VERSION 5.7 ;
  NOWIREEXTENSIONATPIN ON ;
  DIVIDERCHAR "/" ;
  BUSBITCHARS "[]" ;
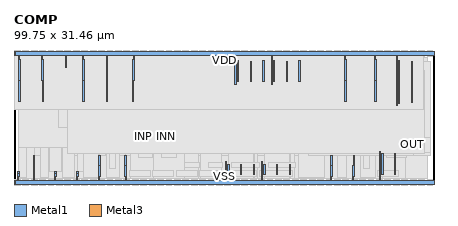
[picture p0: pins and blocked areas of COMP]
MACRO COMP
  CLASS BLOCK ;
  FOREIGN COMP ;
  ORIGIN 1.260 0.000 ;
  SIZE 99.750 BY 31.460 ;
  PIN VSS
    DIRECTION INOUT ;
    USE GROUND ;
    PORT
      LAYER Metal1 ;
        RECT 3.300 4.380 3.660 6.880 ;
        RECT 18.900 4.380 19.260 6.880 ;
        RECT -0.360 2.380 0.000 2.880 ;
        RECT -0.390 1.880 0.000 2.380 ;
        RECT 3.270 1.880 3.660 4.380 ;
        RECT 8.460 2.380 8.820 2.880 ;
        RECT 13.620 2.380 13.980 2.880 ;
        RECT 8.430 1.880 8.820 2.380 ;
        RECT 13.590 1.880 13.980 2.380 ;
        RECT 18.870 1.880 19.260 4.380 ;
        RECT 25.060 4.380 25.420 6.880 ;
        RECT 25.060 1.880 25.450 4.380 ;
        RECT -0.390 0.900 -0.160 1.880 ;
        RECT 3.270 0.900 3.500 1.880 ;
        RECT 8.430 0.900 8.660 1.880 ;
        RECT 13.590 0.900 13.820 1.880 ;
        RECT 18.870 0.900 19.100 1.880 ;
        RECT 25.220 0.900 25.450 1.880 ;
        RECT 48.910 1.650 49.210 5.310 ;
        RECT 49.460 2.230 49.820 4.730 ;
        RECT 52.520 2.250 52.820 4.710 ;
        RECT 55.520 2.230 55.880 4.730 ;
        RECT 57.510 1.650 57.810 5.310 ;
        RECT 58.060 2.230 58.420 4.730 ;
        RECT 61.120 2.250 61.420 4.710 ;
        RECT 64.120 2.230 64.480 4.730 ;
        RECT 73.980 4.380 74.340 6.880 ;
        RECT 79.260 4.380 79.620 6.880 ;
        RECT 73.950 1.880 74.340 4.380 ;
        RECT 79.230 1.880 79.620 4.380 ;
        RECT 48.945 0.900 49.175 1.650 ;
        RECT 57.545 0.900 57.775 1.650 ;
        RECT 73.950 0.900 74.180 1.880 ;
        RECT 79.230 0.900 79.460 1.880 ;
        RECT 85.530 1.650 85.830 7.810 ;
        RECT 86.080 2.230 86.440 7.230 ;
        RECT 89.140 2.250 89.440 7.210 ;
        RECT 85.565 0.900 85.795 1.650 ;
        RECT -1.000 0.000 98.490 0.900 ;
      LAYER Metal3 ;
        RECT -1.260 0.000 98.490 0.900 ;
    END
  END VSS
  PIN VDD
    DIRECTION INOUT ;
    USE POWER ;
    PORT
      LAYER Metal1 ;
        RECT -1.000 30.560 98.490 31.460 ;
        RECT -0.190 29.580 0.040 30.560 ;
        RECT 4.050 30.460 4.530 30.560 ;
        RECT 5.370 29.580 5.600 30.560 ;
        RECT 10.930 29.580 11.160 30.560 ;
        RECT 13.670 30.460 14.150 30.560 ;
        RECT 14.990 29.580 15.220 30.560 ;
        RECT 20.670 29.580 20.900 30.560 ;
        RECT 27.020 29.580 27.250 30.560 ;
        RECT 28.070 30.460 28.550 30.560 ;
        RECT 39.230 30.460 39.710 30.560 ;
        RECT 50.390 30.460 50.870 30.560 ;
        RECT 51.225 29.810 51.455 30.560 ;
        RECT 59.010 30.460 59.490 30.560 ;
        RECT 59.845 29.810 60.075 30.560 ;
        RECT 67.630 30.460 68.110 30.560 ;
        RECT 75.780 30.460 76.260 30.560 ;
        RECT -0.190 24.580 0.200 29.580 ;
        RECT 5.370 24.580 5.760 29.580 ;
        RECT 10.930 28.580 11.320 29.580 ;
        RECT 10.960 27.580 11.320 28.580 ;
        RECT 14.990 24.580 15.380 29.580 ;
        RECT 20.670 24.580 21.060 29.580 ;
        RECT -0.160 19.580 0.200 24.580 ;
        RECT 5.400 19.580 5.760 24.580 ;
        RECT 15.020 19.580 15.380 24.580 ;
        RECT 20.700 19.580 21.060 24.580 ;
        RECT 26.860 24.580 27.250 29.580 ;
        RECT 26.860 19.580 27.220 24.580 ;
        RECT 51.190 23.650 51.490 29.810 ;
        RECT 51.740 24.230 52.100 29.230 ;
        RECT 54.800 24.250 55.100 29.210 ;
        RECT 57.800 24.230 58.160 29.230 ;
        RECT 59.810 23.650 60.110 29.810 ;
        RECT 77.220 29.580 77.450 30.560 ;
        RECT 83.120 30.460 83.600 30.560 ;
        RECT 84.440 29.580 84.670 30.560 ;
        RECT 89.515 29.810 89.745 30.560 ;
        RECT 60.360 24.230 60.720 29.230 ;
        RECT 63.420 24.250 63.720 29.210 ;
        RECT 66.420 24.230 66.780 29.230 ;
        RECT 77.220 24.580 77.610 29.580 ;
        RECT 84.440 24.580 84.830 29.580 ;
        RECT 77.250 19.580 77.610 24.580 ;
        RECT 84.470 19.580 84.830 24.580 ;
        RECT 89.480 18.650 89.780 29.810 ;
        RECT 90.030 19.230 90.390 29.230 ;
        RECT 93.090 19.250 93.390 29.210 ;
      LAYER Metal3 ;
        RECT -1.260 30.560 98.490 31.460 ;
    END
  END VDD
  PIN OUT
    DIRECTION INOUT ;
    ANTENNADIFFAREA 14.400000 ;
    PORT
      LAYER Metal3 ;
      RECT 90.855 9.070 91.255 9.470 ;
      RECT 91.955 9.070 94.855 9.470 ;
      RECT 95.455 9.070 95.855 9.470 ;
    END
  END OUT
  PIN INP
    DIRECTION INPUT ;
    ANTENNAGATEAREA 30.000000 ;
    PORT
      LAYER Metal3 ;
      RECT 28.030 11.050 30.730 11.450 ;
    END
  END INP
  PIN INN
    DIRECTION INPUT ;
    ANTENNAGATEAREA 30.000000 ;
    PORT
      LAYER Metal3 ;
      RECT 33.550 11.050 36.250 11.450 ;
    END
  END INN
  OBS
      LAYER Via1 ;
        RECT -0.160 1.420 96.845 30.040 ;
        RECT 48.850 30.320 50.230 31.700 ;
        RECT 50.850 30.320 52.230 31.700 ;
        RECT 52.850 30.320 54.230 31.700 ;
        RECT 54.850 30.320 56.230 31.700 ;
        RECT 56.850 30.320 58.230 31.700 ;
        RECT 58.850 30.320 60.230 31.700 ;
        RECT 60.850 30.320 62.230 31.700 ;
        RECT 62.850 30.320 64.230 31.700 ;
        RECT 64.850 30.320 66.230 31.700 ;
        RECT 66.850 30.320 68.230 31.700 ;
        RECT 68.850 30.320 70.230 31.700 ;
        RECT 70.850 30.320 72.230 31.700 ;
        RECT 72.850 30.320 74.230 31.700 ;
        RECT 74.850 30.320 76.230 31.700 ;
        RECT 76.850 30.320 78.230 31.700 ;
        RECT 78.850 30.320 80.230 31.700 ;
        RECT 80.850 30.320 82.230 31.700 ;
        RECT 82.850 30.320 84.230 31.700 ;
        RECT 84.850 30.320 86.230 31.700 ;
        RECT 86.850 30.320 88.230 31.700 ;
        RECT 88.850 30.320 90.230 31.700 ;
        RECT 90.850 30.320 92.230 31.700 ;
        RECT 92.850 30.320 94.230 31.700 ;
        RECT 94.850 30.320 96.230 31.700 ;
        RECT 96.850 30.320 98.230 31.700 ;
        RECT -1.150 30.320 0.230 31.700 ;
        RECT 0.850 30.320 2.230 31.700 ;
        RECT 2.850 30.320 4.230 31.700 ;
        RECT 4.850 30.320 6.230 31.700 ;
        RECT 6.850 30.320 8.230 31.700 ;
        RECT 8.850 30.320 10.230 31.700 ;
        RECT 10.850 30.320 12.230 31.700 ;
        RECT 12.850 30.320 14.230 31.700 ;
        RECT 14.850 30.320 16.230 31.700 ;
        RECT 16.850 30.320 18.230 31.700 ;
        RECT 18.850 30.320 20.230 31.700 ;
        RECT 20.850 30.320 22.230 31.700 ;
        RECT 22.850 30.320 24.230 31.700 ;
        RECT 24.850 30.320 26.230 31.700 ;
        RECT 26.850 30.320 28.230 31.700 ;
        RECT 28.850 30.320 30.230 31.700 ;
        RECT 30.850 30.320 32.230 31.700 ;
        RECT 32.850 30.320 34.230 31.700 ;
        RECT 34.850 30.320 36.230 31.700 ;
        RECT 36.850 30.320 38.230 31.700 ;
        RECT 38.850 30.320 40.230 31.700 ;
        RECT 40.850 30.320 42.230 31.700 ;
        RECT 42.850 30.320 44.230 31.700 ;
        RECT 44.850 30.320 46.230 31.700 ;
        RECT 46.850 30.320 48.230 31.700 ;
        RECT 0.850 -0.240 2.230 1.140 ;
        RECT 2.850 -0.240 4.230 1.140 ;
        RECT 4.850 -0.240 6.230 1.140 ;
        RECT 6.850 -0.240 8.230 1.140 ;
        RECT 8.850 -0.240 10.230 1.140 ;
        RECT 10.850 -0.240 12.230 1.140 ;
        RECT 12.850 -0.240 14.230 1.140 ;
        RECT 14.850 -0.240 16.230 1.140 ;
        RECT 16.850 -0.240 18.230 1.140 ;
        RECT 18.850 -0.240 20.230 1.140 ;
        RECT 20.850 -0.240 22.230 1.140 ;
        RECT 22.850 -0.240 24.230 1.140 ;
        RECT 24.850 -0.240 26.230 1.140 ;
        RECT 26.850 -0.240 28.230 1.140 ;
        RECT 28.850 -0.240 30.230 1.140 ;
        RECT 30.850 -0.240 32.230 1.140 ;
        RECT 32.850 -0.240 34.230 1.140 ;
        RECT 34.850 -0.240 36.230 1.140 ;
        RECT 36.850 -0.240 38.230 1.140 ;
        RECT 38.850 -0.240 40.230 1.140 ;
        RECT 40.850 -0.240 42.230 1.140 ;
        RECT 42.850 -0.240 44.230 1.140 ;
        RECT 44.850 -0.240 46.230 1.140 ;
        RECT 46.850 -0.240 48.230 1.140 ;
        RECT -1.150 -0.240 0.230 1.140 ;
        RECT 50.850 -0.240 52.230 1.140 ;
        RECT 52.850 -0.240 54.230 1.140 ;
        RECT 54.850 -0.240 56.230 1.140 ;
        RECT 56.850 -0.240 58.230 1.140 ;
        RECT 58.850 -0.240 60.230 1.140 ;
        RECT 60.850 -0.240 62.230 1.140 ;
        RECT 62.850 -0.240 64.230 1.140 ;
        RECT 64.850 -0.240 66.230 1.140 ;
        RECT 66.850 -0.240 68.230 1.140 ;
        RECT 68.850 -0.240 70.230 1.140 ;
        RECT 70.850 -0.240 72.230 1.140 ;
        RECT 72.850 -0.240 74.230 1.140 ;
        RECT 74.850 -0.240 76.230 1.140 ;
        RECT 76.850 -0.240 78.230 1.140 ;
        RECT 78.850 -0.240 80.230 1.140 ;
        RECT 80.850 -0.240 82.230 1.140 ;
        RECT 82.850 -0.240 84.230 1.140 ;
        RECT 84.850 -0.240 86.230 1.140 ;
        RECT 86.850 -0.240 88.230 1.140 ;
        RECT 88.850 -0.240 90.230 1.140 ;
        RECT 90.850 -0.240 92.230 1.140 ;
        RECT 92.850 -0.240 94.230 1.140 ;
        RECT 94.850 -0.240 96.230 1.140 ;
        RECT 96.850 -0.240 98.230 1.140 ;
        RECT 48.850 -0.240 50.230 1.140 ;
      LAYER Via2 ;
        RECT 48.380 1.820 56.380 3.140 ;
        RECT -0.110 8.590 93.160 17.870 ;
        RECT 45.080 23.820 50.040 25.140 ;
        RECT 47.170 28.320 50.620 29.640 ;
        RECT 50.660 23.820 58.660 25.140 ;
        RECT 59.280 23.820 67.280 25.140 ;
        RECT 79.845 17.920 81.205 25.260 ;
        RECT 88.950 18.820 93.920 20.140 ;
        RECT 52.750 28.320 59.240 29.640 ;
        RECT 61.370 28.320 67.860 29.640 ;
        RECT 91.040 28.320 96.010 29.640 ;
        RECT 48.850 30.320 50.230 31.700 ;
        RECT 50.850 30.320 52.230 31.700 ;
        RECT 52.850 30.320 54.230 31.700 ;
        RECT 54.850 30.320 56.230 31.700 ;
        RECT 56.850 30.320 58.230 31.700 ;
        RECT 58.850 30.320 60.230 31.700 ;
        RECT 60.850 30.320 62.230 31.700 ;
        RECT 62.850 30.320 64.230 31.700 ;
        RECT 64.850 30.320 66.230 31.700 ;
        RECT 66.850 30.320 68.230 31.700 ;
        RECT 68.850 30.320 70.230 31.700 ;
        RECT 70.850 30.320 72.230 31.700 ;
        RECT 72.850 30.320 74.230 31.700 ;
        RECT 74.850 30.320 76.230 31.700 ;
        RECT 76.850 30.320 78.230 31.700 ;
        RECT 78.850 30.320 80.230 31.700 ;
        RECT 80.850 30.320 82.230 31.700 ;
        RECT 82.850 30.320 84.230 31.700 ;
        RECT 84.850 30.320 86.230 31.700 ;
        RECT 86.850 30.320 88.230 31.700 ;
        RECT 88.850 30.320 90.230 31.700 ;
        RECT 90.850 30.320 92.230 31.700 ;
        RECT 92.850 30.320 94.230 31.700 ;
        RECT 94.850 30.320 96.230 31.700 ;
        RECT 96.850 30.320 98.230 31.700 ;
        RECT 34.850 30.320 36.230 31.700 ;
        RECT 36.850 30.320 38.230 31.700 ;
        RECT 38.850 30.320 40.230 31.700 ;
        RECT 40.850 30.320 42.230 31.700 ;
        RECT 42.850 30.320 44.230 31.700 ;
        RECT 44.850 30.320 46.230 31.700 ;
        RECT 46.850 30.320 48.230 31.700 ;
        RECT 30.430 28.320 33.880 29.640 ;
        RECT 36.010 28.320 39.460 29.640 ;
        RECT 41.590 28.320 45.040 29.640 ;
        RECT 28.340 18.820 33.300 20.140 ;
        RECT 39.500 23.820 44.460 25.140 ;
        RECT 23.295 17.920 24.655 25.260 ;
        RECT 33.920 18.820 38.880 20.140 ;
        RECT -1.150 30.320 0.230 31.700 ;
        RECT 0.850 30.320 2.230 31.700 ;
        RECT 2.850 30.320 4.230 31.700 ;
        RECT 4.850 30.320 6.230 31.700 ;
        RECT 6.850 30.320 8.230 31.700 ;
        RECT 8.850 30.320 10.230 31.700 ;
        RECT 10.850 30.320 12.230 31.700 ;
        RECT 12.850 30.320 14.230 31.700 ;
        RECT 14.850 30.320 16.230 31.700 ;
        RECT 16.850 30.320 18.230 31.700 ;
        RECT 18.850 30.320 20.230 31.700 ;
        RECT 20.850 30.320 22.230 31.700 ;
        RECT 22.850 30.320 24.230 31.700 ;
        RECT 24.850 30.320 26.230 31.700 ;
        RECT 26.850 30.320 28.230 31.700 ;
        RECT 28.850 30.320 30.230 31.700 ;
        RECT 30.850 30.320 32.230 31.700 ;
        RECT 32.850 30.320 34.230 31.700 ;
        RECT 21.495 3.700 22.855 8.540 ;
        RECT 0.850 -0.240 2.230 1.140 ;
        RECT 2.850 -0.240 4.230 1.140 ;
        RECT 4.850 -0.240 6.230 1.140 ;
        RECT 6.850 -0.240 8.230 1.140 ;
        RECT 8.850 -0.240 10.230 1.140 ;
        RECT 10.850 -0.240 12.230 1.140 ;
        RECT 12.850 -0.240 14.230 1.140 ;
        RECT 14.850 -0.240 16.230 1.140 ;
        RECT 16.850 -0.240 18.230 1.140 ;
        RECT 18.850 -0.240 20.230 1.140 ;
        RECT 20.850 -0.240 22.230 1.140 ;
        RECT 22.850 -0.240 24.230 1.140 ;
        RECT 24.850 -0.240 26.230 1.140 ;
        RECT 26.850 -0.240 28.230 1.140 ;
        RECT 28.850 -0.240 30.230 1.140 ;
        RECT 30.850 -0.240 32.230 1.140 ;
        RECT 32.850 -0.240 34.230 1.140 ;
        RECT 34.850 -0.240 36.230 1.140 ;
        RECT 36.850 -0.240 38.230 1.140 ;
        RECT 38.850 -0.240 40.230 1.140 ;
        RECT 40.850 -0.240 42.230 1.140 ;
        RECT 42.850 -0.240 44.230 1.140 ;
        RECT 44.850 -0.240 46.230 1.140 ;
        RECT 46.850 -0.240 48.230 1.140 ;
        RECT 26.140 1.820 31.100 3.140 ;
        RECT 31.700 1.820 36.660 3.140 ;
        RECT 37.260 1.820 42.220 3.140 ;
        RECT 42.820 1.820 47.780 3.140 ;
        RECT -1.150 -0.240 0.230 1.140 ;
        RECT 39.350 3.820 42.800 5.140 ;
        RECT 44.910 3.820 48.360 5.140 ;
        RECT 28.230 6.320 31.680 7.640 ;
        RECT 33.790 6.320 37.240 7.640 ;
        RECT 74.850 -0.240 76.230 1.140 ;
        RECT 76.850 -0.240 78.230 1.140 ;
        RECT 78.850 -0.240 80.230 1.140 ;
        RECT 80.850 -0.240 82.230 1.140 ;
        RECT 82.850 -0.240 84.230 1.140 ;
        RECT 84.850 -0.240 86.230 1.140 ;
        RECT 86.850 -0.240 88.230 1.140 ;
        RECT 88.850 -0.240 90.230 1.140 ;
        RECT 90.850 -0.240 92.230 1.140 ;
        RECT 92.850 -0.240 94.230 1.140 ;
        RECT 94.850 -0.240 96.230 1.140 ;
        RECT 96.850 -0.240 98.230 1.140 ;
        RECT 48.850 -0.240 50.230 1.140 ;
        RECT 50.850 -0.240 52.230 1.140 ;
        RECT 52.850 -0.240 54.230 1.140 ;
        RECT 54.850 -0.240 56.230 1.140 ;
        RECT 56.850 -0.240 58.230 1.140 ;
        RECT 56.980 1.820 64.980 3.140 ;
        RECT 85.000 1.820 89.970 3.140 ;
        RECT 58.850 -0.240 60.230 1.140 ;
        RECT 60.850 -0.240 62.230 1.140 ;
        RECT 50.470 3.820 56.960 5.140 ;
        RECT 59.070 3.820 65.560 5.140 ;
        RECT 62.850 -0.240 64.230 1.140 ;
        RECT 64.850 -0.240 66.230 1.140 ;
        RECT 87.090 6.320 92.060 7.640 ;
        RECT 66.850 -0.240 68.230 1.140 ;
        RECT 81.855 3.700 83.215 8.540 ;
        RECT 89.865 8.580 96.845 9.960 ;
        RECT 68.850 -0.240 70.230 1.140 ;
        RECT 70.850 -0.240 72.230 1.140 ;
        RECT 72.850 -0.240 74.230 1.140 ;
      LAYER Via3 ;
        RECT 93.765 7.380 97.545 11.160 ;
        RECT 62.310 8.700 66.090 12.480 ;
        RECT 68.765 6.780 93.545 22.460 ;
        RECT 9.410 13.380 34.190 29.060 ;
      LAYER Via4 ;
        RECT 9.410 6.780 97.545 29.060 ;
      LAYER Metal1 ;
        RECT -0.160 1.650 1.815 9.670 ;
        RECT 3.500 6.870 4.960 10.330 ;
        RECT 5.000 1.650 6.975 10.330 ;
        RECT 19.100 6.870 20.560 10.330 ;
        RECT 23.760 6.870 25.220 10.330 ;
        RECT 74.180 6.870 75.640 10.330 ;
        RECT 20.600 1.650 23.720 10.990 ;
        RECT 64.480 1.420 65.280 10.990 ;
        RECT 55.880 1.420 56.680 11.650 ;
        RECT 43.100 1.420 48.080 13.630 ;
        RECT 86.280 1.420 91.780 13.630 ;
        RECT 80.960 1.650 84.595 14.950 ;
        RECT 37.540 1.420 42.520 15.610 ;
        RECT 49.660 1.420 55.680 15.610 ;
        RECT 58.260 1.420 64.280 15.610 ;
        RECT 75.680 1.650 77.655 16.270 ;
        RECT 13.820 2.870 15.280 17.590 ;
        RECT 0.040 16.130 1.500 19.590 ;
        RECT 5.600 16.130 7.060 19.590 ;
        RECT 20.900 16.130 22.360 19.590 ;
        RECT 25.560 16.130 27.020 19.590 ;
        RECT 77.450 10.190 78.910 19.590 ;
        RECT 84.670 16.130 86.130 19.590 ;
        RECT 1.540 8.870 3.515 29.810 ;
        RECT 7.100 2.870 10.120 29.810 ;
        RECT 10.160 1.650 13.135 29.810 ;
        RECT 15.165 1.650 18.695 29.810 ;
        RECT 22.400 11.510 25.520 29.810 ;
        RECT 72.755 12.830 75.245 29.810 ;
        RECT 78.950 6.870 82.585 29.810 ;
        RECT 86.170 14.150 88.145 29.810 ;
        RECT 26.420 1.420 33.600 30.040 ;
        RECT 31.980 1.420 39.180 30.040 ;
        RECT 39.780 11.510 44.760 30.040 ;
        RECT 45.360 13.490 50.340 30.040 ;
        RECT 51.940 12.170 57.960 30.040 ;
        RECT 58.160 11.510 58.960 30.040 ;
        RECT 60.560 12.170 66.580 30.040 ;
        RECT 66.345 1.650 72.495 30.040 ;
        RECT 90.230 8.870 95.730 30.040 ;
      LAYER Metal2 ;
        RECT 48.380 1.820 56.380 3.140 ;
        RECT -0.110 8.590 93.160 17.870 ;
        RECT 45.080 23.820 50.040 25.140 ;
        RECT 47.170 28.320 50.620 29.640 ;
        RECT 50.660 23.820 58.660 25.140 ;
        RECT 59.280 23.820 67.280 25.140 ;
        RECT 79.845 17.920 81.205 25.260 ;
        RECT 88.950 18.820 93.920 20.140 ;
        RECT 52.750 28.320 59.240 29.640 ;
        RECT 61.370 28.320 67.860 29.640 ;
        RECT 91.040 28.320 96.010 29.640 ;
        RECT 48.850 30.320 50.230 31.700 ;
        RECT 50.850 30.320 52.230 31.700 ;
        RECT 52.850 30.320 54.230 31.700 ;
        RECT 54.850 30.320 56.230 31.700 ;
        RECT 56.850 30.320 58.230 31.700 ;
        RECT 58.850 30.320 60.230 31.700 ;
        RECT 60.850 30.320 62.230 31.700 ;
        RECT 62.850 30.320 64.230 31.700 ;
        RECT 64.850 30.320 66.230 31.700 ;
        RECT 66.850 30.320 68.230 31.700 ;
        RECT 68.850 30.320 70.230 31.700 ;
        RECT 70.850 30.320 72.230 31.700 ;
        RECT 72.850 30.320 74.230 31.700 ;
        RECT 74.850 30.320 76.230 31.700 ;
        RECT 76.850 30.320 78.230 31.700 ;
        RECT 78.850 30.320 80.230 31.700 ;
        RECT 80.850 30.320 82.230 31.700 ;
        RECT 82.850 30.320 84.230 31.700 ;
        RECT 84.850 30.320 86.230 31.700 ;
        RECT 86.850 30.320 88.230 31.700 ;
        RECT 88.850 30.320 90.230 31.700 ;
        RECT 90.850 30.320 92.230 31.700 ;
        RECT 92.850 30.320 94.230 31.700 ;
        RECT 94.850 30.320 96.230 31.700 ;
        RECT 96.850 30.320 98.230 31.700 ;
        RECT 34.850 30.320 36.230 31.700 ;
        RECT 36.850 30.320 38.230 31.700 ;
        RECT 38.850 30.320 40.230 31.700 ;
        RECT 40.850 30.320 42.230 31.700 ;
        RECT 42.850 30.320 44.230 31.700 ;
        RECT 44.850 30.320 46.230 31.700 ;
        RECT 46.850 30.320 48.230 31.700 ;
        RECT 30.430 28.320 33.880 29.640 ;
        RECT 36.010 28.320 39.460 29.640 ;
        RECT 41.590 28.320 45.040 29.640 ;
        RECT 28.340 18.820 33.300 20.140 ;
        RECT 39.500 23.820 44.460 25.140 ;
        RECT 23.295 17.920 24.655 25.260 ;
        RECT 33.920 18.820 38.880 20.140 ;
        RECT -1.150 30.320 0.230 31.700 ;
        RECT 0.850 30.320 2.230 31.700 ;
        RECT 2.850 30.320 4.230 31.700 ;
        RECT 4.850 30.320 6.230 31.700 ;
        RECT 6.850 30.320 8.230 31.700 ;
        RECT 8.850 30.320 10.230 31.700 ;
        RECT 10.850 30.320 12.230 31.700 ;
        RECT 12.850 30.320 14.230 31.700 ;
        RECT 14.850 30.320 16.230 31.700 ;
        RECT 16.850 30.320 18.230 31.700 ;
        RECT 18.850 30.320 20.230 31.700 ;
        RECT 20.850 30.320 22.230 31.700 ;
        RECT 22.850 30.320 24.230 31.700 ;
        RECT 24.850 30.320 26.230 31.700 ;
        RECT 26.850 30.320 28.230 31.700 ;
        RECT 28.850 30.320 30.230 31.700 ;
        RECT 30.850 30.320 32.230 31.700 ;
        RECT 32.850 30.320 34.230 31.700 ;
        RECT 21.495 3.700 22.855 8.540 ;
        RECT 0.850 -0.240 2.230 1.140 ;
        RECT 2.850 -0.240 4.230 1.140 ;
        RECT 4.850 -0.240 6.230 1.140 ;
        RECT 6.850 -0.240 8.230 1.140 ;
        RECT 8.850 -0.240 10.230 1.140 ;
        RECT 10.850 -0.240 12.230 1.140 ;
        RECT 12.850 -0.240 14.230 1.140 ;
        RECT 14.850 -0.240 16.230 1.140 ;
        RECT 16.850 -0.240 18.230 1.140 ;
        RECT 18.850 -0.240 20.230 1.140 ;
        RECT 20.850 -0.240 22.230 1.140 ;
        RECT 22.850 -0.240 24.230 1.140 ;
        RECT 24.850 -0.240 26.230 1.140 ;
        RECT 26.850 -0.240 28.230 1.140 ;
        RECT 28.850 -0.240 30.230 1.140 ;
        RECT 30.850 -0.240 32.230 1.140 ;
        RECT 32.850 -0.240 34.230 1.140 ;
        RECT 34.850 -0.240 36.230 1.140 ;
        RECT 36.850 -0.240 38.230 1.140 ;
        RECT 38.850 -0.240 40.230 1.140 ;
        RECT 40.850 -0.240 42.230 1.140 ;
        RECT 42.850 -0.240 44.230 1.140 ;
        RECT 44.850 -0.240 46.230 1.140 ;
        RECT 46.850 -0.240 48.230 1.140 ;
        RECT 26.140 1.820 31.100 3.140 ;
        RECT 31.700 1.820 36.660 3.140 ;
        RECT 37.260 1.820 42.220 3.140 ;
        RECT 42.820 1.820 47.780 3.140 ;
        RECT -1.150 -0.240 0.230 1.140 ;
        RECT 39.350 3.820 42.800 5.140 ;
        RECT 44.910 3.820 48.360 5.140 ;
        RECT 28.230 6.320 31.680 7.640 ;
        RECT 33.790 6.320 37.240 7.640 ;
        RECT 74.850 -0.240 76.230 1.140 ;
        RECT 76.850 -0.240 78.230 1.140 ;
        RECT 78.850 -0.240 80.230 1.140 ;
        RECT 80.850 -0.240 82.230 1.140 ;
        RECT 82.850 -0.240 84.230 1.140 ;
        RECT 84.850 -0.240 86.230 1.140 ;
        RECT 86.850 -0.240 88.230 1.140 ;
        RECT 88.850 -0.240 90.230 1.140 ;
        RECT 90.850 -0.240 92.230 1.140 ;
        RECT 92.850 -0.240 94.230 1.140 ;
        RECT 94.850 -0.240 96.230 1.140 ;
        RECT 96.850 -0.240 98.230 1.140 ;
        RECT 48.850 -0.240 50.230 1.140 ;
        RECT 50.850 -0.240 52.230 1.140 ;
        RECT 52.850 -0.240 54.230 1.140 ;
        RECT 54.850 -0.240 56.230 1.140 ;
        RECT 56.850 -0.240 58.230 1.140 ;
        RECT 56.980 1.820 64.980 3.140 ;
        RECT 85.000 1.820 89.970 3.140 ;
        RECT 58.850 -0.240 60.230 1.140 ;
        RECT 60.850 -0.240 62.230 1.140 ;
        RECT 50.470 3.820 56.960 5.140 ;
        RECT 59.070 3.820 65.560 5.140 ;
        RECT 62.850 -0.240 64.230 1.140 ;
        RECT 64.850 -0.240 66.230 1.140 ;
        RECT 87.090 6.320 92.060 7.640 ;
        RECT 66.850 -0.240 68.230 1.140 ;
        RECT 81.855 3.700 83.215 8.540 ;
        RECT 89.865 8.580 96.845 9.960 ;
        RECT 68.850 -0.240 70.230 1.140 ;
        RECT 70.850 -0.240 72.230 1.140 ;
        RECT 72.850 -0.240 74.230 1.140 ;
      LAYER Metal3 ;
        RECT 63.510 9.900 64.890 11.280 ;
        RECT 31.010 15.180 32.390 16.560 ;
      LAYER Metal4 ;
        RECT 93.765 7.380 97.545 11.160 ;
        RECT 62.310 8.700 66.090 12.480 ;
        RECT 68.765 6.780 93.545 22.460 ;
        RECT 9.410 13.380 34.190 29.060 ;
      LAYER Metal5 ;
        RECT 63.600 9.870 91.355 20.470 ;
        RECT 11.400 7.270 96.255 27.070 ;
      LAYER Nwell ;
        RECT -1.260 17.750 96.030 31.460 ;
  END
END COMP
